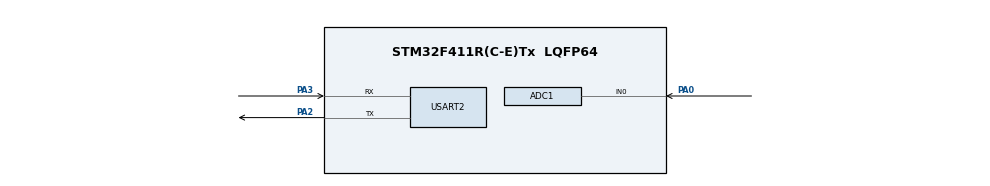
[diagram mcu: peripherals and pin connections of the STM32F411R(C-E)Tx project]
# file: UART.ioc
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ADC1.Channel-0\#ChannelRegularConversion=ADC_CHANNEL_0
ADC1.ClockPrescaler=ADC_CLOCK_SYNC_PCLK_DIV8
ADC1.ContinuousConvMode=ENABLE
ADC1.DMAContinuousRequests=ENABLE
ADC1.DataAlign=ADC_DATAALIGN_RIGHT
ADC1.DiscontinuousConvMode=DISABLE
ADC1.EOCSelection=ADC_EOC_SINGLE_CONV
ADC1.EnableAnalogWatchDog=false
ADC1.ExternalTrigConv=ADC_SOFTWARE_START
ADC1.ExternalTrigConvEdge=ADC_EXTERNALTRIGCONVEDGE_NONE
ADC1.InjNumberOfConversion=0
ADC1.NbrOfConversion=1
ADC1.NbrOfConversionFlag=1
ADC1.Rank-0\#ChannelRegularConversion=1
ADC1.Resolution=ADC_RESOLUTION_8B
ADC1.SamplingTime-0\#ChannelRegularConversion=ADC_SAMPLETIME_480CYCLES
ADC1.ScanConvMode=DISABLE
ADC1.master=1
Dma.ADC1.1.Direction=DMA_PERIPH_TO_MEMORY
Dma.ADC1.1.FIFOMode=DMA_FIFOMODE_DISABLE
Dma.ADC1.1.Instance=DMA2_Stream0
Dma.ADC1.1.MemDataAlignment=DMA_MDATAALIGN_BYTE
Dma.ADC1.1.MemInc=DMA_MINC_ENABLE
Dma.ADC1.1.Mode=DMA_CIRCULAR
Dma.ADC1.1.PeriphDataAlignment=DMA_PDATAALIGN_BYTE
Dma.ADC1.1.PeriphInc=DMA_PINC_DISABLE
Dma.ADC1.1.Priority=DMA_PRIORITY_LOW
Dma.Request0=USART2_TX
Dma.Request1=ADC1
Dma.USART2_TX.0.Direction=DMA_MEMORY_TO_PERIPH
Dma.USART2_TX.0.FIFOMode=DMA_FIFOMODE_DISABLE
Dma.USART2_TX.0.Instance=DMA1_Stream6
Dma.USART2_TX.0.MemDataAlignment=DMA_MDATAALIGN_BYTE
Dma.USART2_TX.0.MemInc=DMA_MINC_ENABLE
Dma.USART2_TX.0.Mode=DMA_CIRCULAR
Dma.USART2_TX.0.PeriphDataAlignment=DMA_PDATAALIGN_BYTE
Dma.USART2_TX.0.PeriphInc=DMA_PINC_DISABLE
Dma.USART2_TX.0.Priority=DMA_PRIORITY_LOW
Mcu.Family=STM32F4
Mcu.Name=STM32F411R(C-E)Tx
Mcu.Package=LQFP64
NVIC.DMA1_Stream6_IRQn=true\:0\:0\:false\:false\:true\:false
NVIC.DMA2_Stream0_IRQn=true\:0\:0\:false\:false\:true\:false
NVIC.PriorityGroup=NVIC_PRIORITYGROUP_0
NVIC.USART2_IRQn=true\:0\:0\:false\:false\:true\:true
PA0-WKUP.Signal=ADCx_IN0
PA2.Mode=Asynchronous
PA2.Signal=USART2_TX
PA3.Mode=Asynchronous
PA3.Signal=USART2_RX
PH0\ -\ OSC_IN.Mode=HSE-External-Oscillator
PH0\ -\ OSC_IN.Signal=RCC_OSC_IN
PH1\ -\ OSC_OUT.Mode=HSE-External-Oscillator
PH1\ -\ OSC_OUT.Signal=RCC_OSC_OUT
ProjectManager.HeapSize=0x200
ProjectManager.StackSize=0x400
ProjectManager.TargetToolchain=SW4STM32
RCC.48MHZClocksFreq_Value=50000000
RCC.AHBFreq_Value=100000000
RCC.APB1CLKDivider=RCC_HCLK_DIV2
RCC.APB1Freq_Value=50000000
RCC.APB1TimFreq_Value=100000000
RCC.APB2CLKDivider=RCC_HCLK_DIV2
RCC.APB2Freq_Value=50000000
RCC.APB2TimFreq_Value=100000000
RCC.CortexFreq_Value=100000000
RCC.FLatency-AdvancedSettings=FLASH_LATENCY_3
RCC.HCLKFreq_Value=100000000
RCC.HSE_VALUE=8000000
RCC.HSI_VALUE=16000000
RCC.LSE_VALUE=32768
RCC.PLLM=4
RCC.PLLN=100
RCC.PLLSourceVirtual=RCC_PLLSOURCE_HSE
RCC.SYSCLKFreq_VALUE=100000000
RCC.SYSCLKSource=RCC_SYSCLKSOURCE_PLLCLK
RCC.VCOOutputFreq_Value=200000000
SH.ADCx_IN0.0=ADC1_IN0,IN0
USART2.OverSampling=UART_OVERSAMPLING_16
USART2.VirtualMode=VM_ASYNC
board=NUCLEO-F411RE

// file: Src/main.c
/**
  ******************************************************************************
  * File Name          : main.c
  * Description        : Main program body
  ******************************************************************************
  ** This notice applies to any and all portions of this file
  * that are not between comment pairs USER CODE BEGIN and
  * USER CODE END. Other portions of this file, whether
  * inserted by the user or by software development tools
  * are owned by their respective copyright owners.
  *
  * COPYRIGHT(c) 2017 STMicroelectronics
  *
  * Redistribution and use in source and binary forms, with or without modification,
  * are permitted provided that the following conditions are met:
  *   1. Redistributions of source code must retain the above copyright notice,
  *      this list of conditions and the following disclaimer.
  *   2. Redistributions in binary form must reproduce the above copyright notice,
  *      this list of conditions and the following disclaimer in the documentation
  *      and/or other materials provided with the distribution.
  *   3. Neither the name of STMicroelectronics nor the names of its contributors
  *      may be used to endorse or promote products derived from this software
  *      without specific prior written permission.
  *
  * THIS SOFTWARE IS PROVIDED BY THE COPYRIGHT HOLDERS AND CONTRIBUTORS "AS IS"
  * AND ANY EXPRESS OR IMPLIED WARRANTIES, INCLUDING, BUT NOT LIMITED TO, THE
  * IMPLIED WARRANTIES OF MERCHANTABILITY AND FITNESS FOR A PARTICULAR PURPOSE ARE
  * DISCLAIMED. IN NO EVENT SHALL THE COPYRIGHT HOLDER OR CONTRIBUTORS BE LIABLE
  * FOR ANY DIRECT, INDIRECT, INCIDENTAL, SPECIAL, EXEMPLARY, OR CONSEQUENTIAL
  * DAMAGES (INCLUDING, BUT NOT LIMITED TO, PROCUREMENT OF SUBSTITUTE GOODS OR
  * SERVICES; LOSS OF USE, DATA, OR PROFITS; OR BUSINESS INTERRUPTION) HOWEVER
  * CAUSED AND ON ANY THEORY OF LIABILITY, WHETHER IN CONTRACT, STRICT LIABILITY,
  * OR TORT (INCLUDING NEGLIGENCE OR OTHERWISE) ARISING IN ANY WAY OUT OF THE USE
  * OF THIS SOFTWARE, EVEN IF ADVISED OF THE POSSIBILITY OF SUCH DAMAGE.
  *
  ******************************************************************************
  */
#include "main.h"
#include "stm32f4xx_hal.h"

/* USER CODE BEGIN Includes */
uint8_t buffor[8];
uint16_t length,i;
/* USER CODE END Includes */

ADC_HandleTypeDef hadc1;
DMA_HandleTypeDef hdma_adc1;

UART_HandleTypeDef huart2;
DMA_HandleTypeDef hdma_usart2_tx;

/* USER CODE BEGIN PV */
/* Private variables ---------------------------------------------------------*/

/* USER CODE END PV */

void SystemClock_Config(void);
static void MX_GPIO_Init(void);
static void MX_DMA_Init(void);
static void MX_ADC1_Init(void);
static void MX_USART2_UART_Init(void);

/* USER CODE BEGIN PFP */
/* Private function prototypes -----------------------------------------------*/

/* USER CODE END PFP */

int main(void)
{

  /* MCU Configuration----------------------------------------------------------*/

  /* Reset of all peripherals, Initializes the Flash interface and the Systick. */
  HAL_Init();

  /* Configure the system clock */
  SystemClock_Config();

  /* Initialize all configured peripherals */
  MX_GPIO_Init();
  MX_DMA_Init();
  MX_ADC1_Init();
  MX_USART2_UART_Init();

  /* USER CODE BEGIN 2 */
  //for (i=0; i<256; i++){
	//  buffor[i] = i;
  //}
  length = sizeof(buffor);
  HAL_ADC_Start_DMA(&hadc1, (uint32_t*)buffor, length);
  HAL_UART_Transmit_DMA(&huart2, buffor, length);
  /* USER CODE END 2 */

  /* Infinite loop */
  while (1)
  {

  }

}

/** System Clock Configuration
*/
void SystemClock_Config(void)
{

  RCC_OscInitTypeDef RCC_OscInitStruct;
  RCC_ClkInitTypeDef RCC_ClkInitStruct;

    /**Configure the main internal regulator output voltage
    */
  __HAL_RCC_PWR_CLK_ENABLE();

  __HAL_PWR_VOLTAGESCALING_CONFIG(PWR_REGULATOR_VOLTAGE_SCALE1);

    /**Initializes the CPU, AHB and APB busses clocks
    */
  RCC_OscInitStruct.OscillatorType = RCC_OSCILLATORTYPE_HSE;
  RCC_OscInitStruct.HSEState = RCC_HSE_ON;
  RCC_OscInitStruct.PLL.PLLState = RCC_PLL_ON;
  RCC_OscInitStruct.PLL.PLLSource = RCC_PLLSOURCE_HSE;
  RCC_OscInitStruct.PLL.PLLM = 4;
  RCC_OscInitStruct.PLL.PLLN = 60;
  RCC_OscInitStruct.PLL.PLLP = RCC_PLLP_DIV2;
  RCC_OscInitStruct.PLL.PLLQ = 4;
  if (HAL_RCC_OscConfig(&RCC_OscInitStruct) != HAL_OK)
  {
    _Error_Handler(__FILE__, __LINE__);
  }

    /**Initializes the CPU, AHB and APB busses clocks
    */
  RCC_ClkInitStruct.ClockType = RCC_CLOCKTYPE_HCLK|RCC_CLOCKTYPE_SYSCLK
                              |RCC_CLOCKTYPE_PCLK1|RCC_CLOCKTYPE_PCLK2;
  RCC_ClkInitStruct.SYSCLKSource = RCC_SYSCLKSOURCE_PLLCLK;
  RCC_ClkInitStruct.AHBCLKDivider = RCC_SYSCLK_DIV1;
  RCC_ClkInitStruct.APB1CLKDivider = RCC_HCLK_DIV4;
  RCC_ClkInitStruct.APB2CLKDivider = RCC_HCLK_DIV2;

  if (HAL_RCC_ClockConfig(&RCC_ClkInitStruct, FLASH_LATENCY_1) != HAL_OK)
  {
    _Error_Handler(__FILE__, __LINE__);
  }

    /**Configure the Systick interrupt time
    */
  HAL_SYSTICK_Config(HAL_RCC_GetHCLKFreq()/1000);

    /**Configure the Systick
    */
  HAL_SYSTICK_CLKSourceConfig(SYSTICK_CLKSOURCE_HCLK);

  /* SysTick_IRQn interrupt configuration */
  HAL_NVIC_SetPriority(SysTick_IRQn, 0, 0);
}

/* ADC1 init function */
static void MX_ADC1_Init(void)
{

  ADC_ChannelConfTypeDef sConfig;

    /**Configure the global features of the ADC (Clock, Resolution, Data Alignment and number of conversion)
    */
  hadc1.Instance = ADC1;
  hadc1.Init.ClockPrescaler = ADC_CLOCK_SYNC_PCLK_DIV8;
  hadc1.Init.Resolution = ADC_RESOLUTION_8B;
  hadc1.Init.ScanConvMode = DISABLE;
  hadc1.Init.ContinuousConvMode = ENABLE;
  hadc1.Init.DiscontinuousConvMode = DISABLE;
  hadc1.Init.ExternalTrigConvEdge = ADC_EXTERNALTRIGCONVEDGE_NONE;
  hadc1.Init.ExternalTrigConv = ADC_SOFTWARE_START;
  hadc1.Init.DataAlign = ADC_DATAALIGN_RIGHT;
  hadc1.Init.NbrOfConversion = 1;
  hadc1.Init.DMAContinuousRequests = ENABLE;
  hadc1.Init.EOCSelection = ADC_EOC_SINGLE_CONV;
  if (HAL_ADC_Init(&hadc1) != HAL_OK)
  {
    _Error_Handler(__FILE__, __LINE__);
  }

    /**Configure for the selected ADC regular channel its corresponding rank in the sequencer and its sample time.
    */
  sConfig.Channel = ADC_CHANNEL_0;
  sConfig.Rank = 1;
  sConfig.SamplingTime = ADC_SAMPLETIME_480CYCLES;
  if (HAL_ADC_ConfigChannel(&hadc1, &sConfig) != HAL_OK)
  {
    _Error_Handler(__FILE__, __LINE__);
  }

}

/* USART2 init function */
static void MX_USART2_UART_Init(void)
{

  huart2.Instance = USART2;
  huart2.Init.BaudRate = 115200;
  huart2.Init.WordLength = UART_WORDLENGTH_8B;
  huart2.Init.StopBits = UART_STOPBITS_1;
  huart2.Init.Parity = UART_PARITY_NONE;
  huart2.Init.Mode = UART_MODE_TX_RX;
  huart2.Init.HwFlowCtl = UART_HWCONTROL_NONE;
  huart2.Init.OverSampling = UART_OVERSAMPLING_16;
  if (HAL_UART_Init(&huart2) != HAL_OK)
  {
    _Error_Handler(__FILE__, __LINE__);
  }

}

static void MX_DMA_Init(void)
{
  /* DMA controller clock enable */
  __HAL_RCC_DMA2_CLK_ENABLE();
  __HAL_RCC_DMA1_CLK_ENABLE();

  /* DMA interrupt init */
  /* DMA1_Stream6_IRQn interrupt configuration */
  HAL_NVIC_SetPriority(DMA1_Stream6_IRQn, 0, 0);
  HAL_NVIC_EnableIRQ(DMA1_Stream6_IRQn);
  /* DMA2_Stream0_IRQn interrupt configuration */
  HAL_NVIC_SetPriority(DMA2_Stream0_IRQn, 0, 0);
  HAL_NVIC_EnableIRQ(DMA2_Stream0_IRQn);

}

/** Configure pins as
        * Analog
        * Input
        * Output
        * EVENT_OUT
        * EXTI
*/
static void MX_GPIO_Init(void)
{

  /* GPIO Ports Clock Enable */
  __HAL_RCC_GPIOH_CLK_ENABLE();
  __HAL_RCC_GPIOA_CLK_ENABLE();

}

void _Error_Handler(char * file, int line)
{
  while(1)
  {
  }
}

/************************ (C) COPYRIGHT STMicroelectronics *****END OF FILE****/
